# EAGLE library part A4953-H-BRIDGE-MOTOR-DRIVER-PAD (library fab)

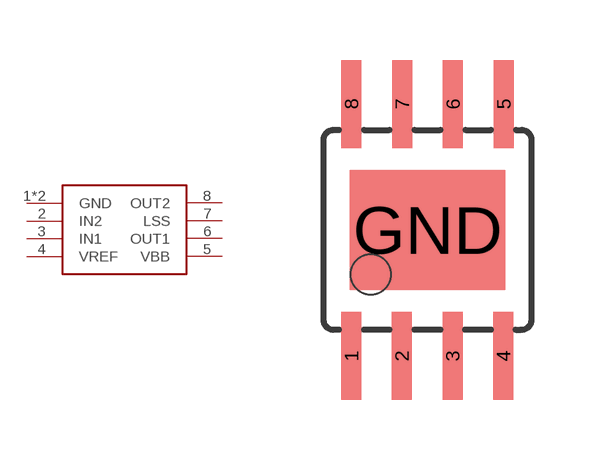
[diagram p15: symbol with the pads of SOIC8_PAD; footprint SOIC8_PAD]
Designator prefix -

## A4953-H-BRIDGE-MOTOR-DRIVER-PAD  [SOIC8_PAD]
1  GND
2  IN2
3  IN1
4  VREF
5  VBB
6  OUT1
7  LSS
8  OUT2
GND  GND

## Footprint SOIC8_PAD (pad centres in mm)
Wide Plastic Gull Wing Small Outline Package
smd 0.5 x 2.2: 1 -1.905,-3.154; 2 -0.645,-3.154; 3 0.625,-3.154; 4 1.895,-3.154; 5 1.905,3.154; 6 0.635,3.154; 7 -0.635,3.154; 8 -1.905,3.154
smd 3.886 x 2.997: GND 0,0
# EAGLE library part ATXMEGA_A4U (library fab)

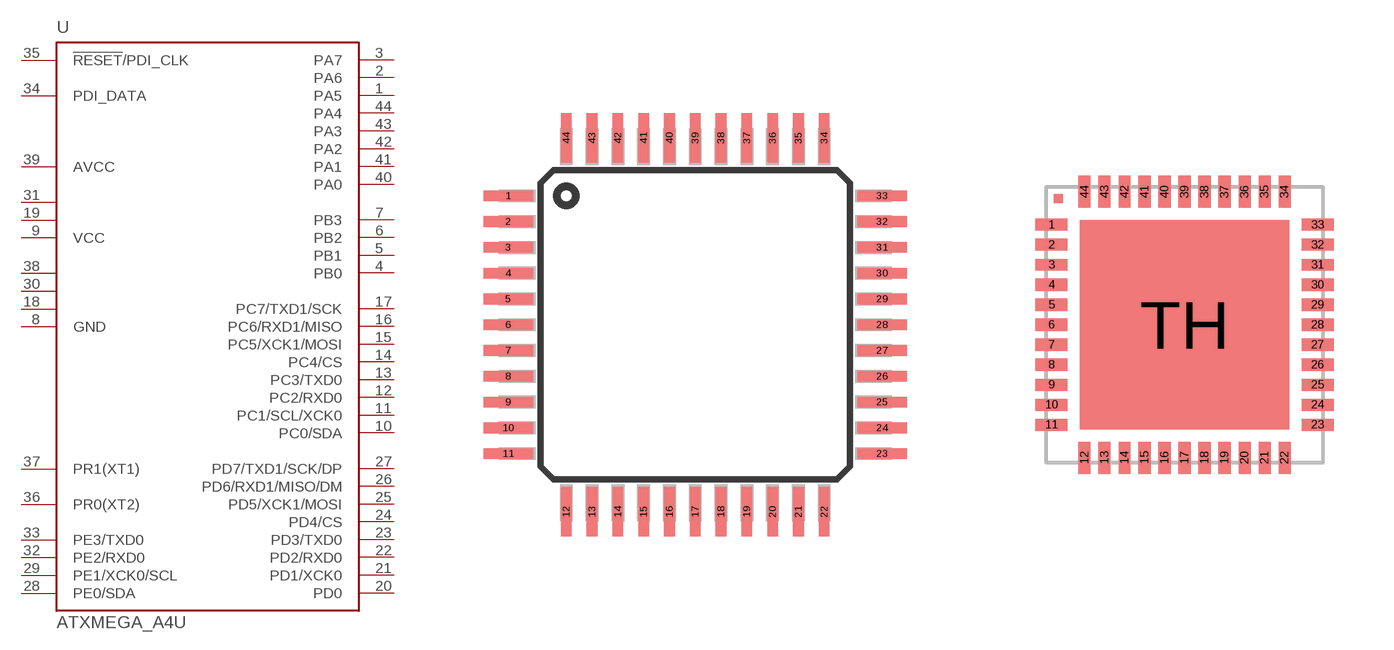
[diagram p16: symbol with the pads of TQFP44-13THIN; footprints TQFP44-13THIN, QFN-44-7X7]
Designator prefix -

## ATXMEGA_A4UTQFP-44-1-64  [TQFP44-13THIN]
1  PA5
2  PA6
3  PA7
4  PB0
5  PB1
6  PB2
7  PB3
8  GND  pwr
9  VCC  pwr
10  PC0/SDA
11  PC1/SCL/XCK0
12  PC2/RXD0
13  PC3/TXD0
14  PC4/CS
15  PC5/XCK1/MOSI
16  PC6/RXD1/MISO
17  PC7/TXD1/SCK
18  GND1  pwr
19  VCC1  pwr
20  PD0
21  PD1/XCK0
22  PD2/RXD0
23  PD3/TXD0
24  PD4/CS
25  PD5/XCK1/MOSI
26  PD6/RXD1/MISO/DM
27  PD7/TXD1/SCK/DP
28  PE0/SDA
29  PE1/XCK0/SCL
30  GND2  pwr
31  VCC2  pwr
32  PE2/RXD0
33  PE3/TXD0
34  PDI_DATA
35  !RESET!/PDI_CLK
36  PR0(XT2)
37  PR1(XT1)
38  GND3  pwr
39  AVCC  pwr
40  PA0
41  PA1
42  PA2
43  PA3
44  PA4

## ATXMEGA_A4UVFQFN-44  [QFN-44-7X7]
1  PA5
2  PA6
3  PA7
4  PB0
5  PB1
6  PB2
7  PB3
8  GND  pwr
9  VCC  pwr
10  PC0/SDA
11  PC1/SCL/XCK0
12  PC2/RXD0
13  PC3/TXD0
14  PC4/CS
15  PC5/XCK1/MOSI
16  PC6/RXD1/MISO
17  PC7/TXD1/SCK
18  GND1  pwr
19  VCC1  pwr
20  PD0
21  PD1/XCK0
22  PD2/RXD0
23  PD3/TXD0
24  PD4/CS
25  PD5/XCK1/MOSI
26  PD6/RXD1/MISO/DM
27  PD7/TXD1/SCK/DP
28  PE0/SDA
29  PE1/XCK0/SCL
30  GND2  pwr
31  VCC2  pwr
32  PE2/RXD0
33  PE3/TXD0
34  PDI_DATA
35  !RESET!/PDI_CLK
36  PR0(XT2)
37  PR1(XT1)
38  GND3  pwr
39  AVCC  pwr
40  PA0
41  PA1
42  PA2
43  PA3
44  PA4
TH  GND  pwr

## Footprint TQFP44-13THIN (pad centres in mm)
Thin Quad Flat Pack package type TQ
smd 1.524 x 0.33: 1 -5.8,4; 2 -5.8,3.2; 3 -5.8,2.4; 4 -5.8,1.6; 5 -5.8,0.8; 6 -5.8,0; 7 -5.8,-0.8; 8 -5.8,-1.6; 9 -5.8,-2.4; 10 -5.8,-3.2; 11 -5.8,-4; 23 5.8,-4; 24 5.8,-3.2; 25 5.8,-2.4; 26 5.8,-1.6; 27 5.8,-0.8; 28 5.8,0; 29 5.8,0.8; 30 5.8,1.6; 31 5.8,2.4; 32 5.8,3.2; 33 5.8,4
smd 0.33 x 1.524: 12 -4,-5.8; 13 -3.2,-5.8; 14 -2.4,-5.8; 15 -1.6,-5.8; 16 -0.8,-5.8; 17 0,-5.8; 18 0.8,-5.8; 19 1.6,-5.8; 20 2.4,-5.8; 21 3.2,-5.8; 22 4,-5.8; 34 4,5.8; 35 3.2,5.8; 36 2.4,5.8; 37 1.6,5.8; 38 0.8,5.8; 39 0,5.8; 40 -0.8,5.8; 41 -1.6,5.8; 42 -2.4,5.8; 43 -3.2,5.8; 44 -4,5.8

## Footprint QFN-44-7X7 (pad centres in mm)
QFN-44 (7x7x1.8mm) Source: http://www.st.com/stonline/products/literature/ds/11020.pdf
smd 0.8 x 0.3: 1 -3.325,2.5; 2 -3.325,2; 3 -3.325,1.5; 4 -3.325,1; 5 -3.325,0.5; 6 -3.325,0; 7 -3.325,-0.5; 8 -3.325,-1; 9 -3.325,-1.5; 10 -3.325,-2; 11 -3.325,-2.5; 23 3.325,-2.5; 24 3.325,-2; 25 3.325,-1.5; 26 3.325,-1; 27 3.325,-0.5; 28 3.325,0; 29 3.325,0.5; 30 3.325,1; 31 3.325,1.5; 32 3.325,2; 33 3.325,2.5
smd 0.3 x 0.8: 12 -2.5,-3.325; 13 -2,-3.325; 14 -1.5,-3.325; 15 -1,-3.325; 16 -0.5,-3.325; 17 0,-3.325; 18 0.5,-3.325; 19 1,-3.325; 20 1.5,-3.325; 21 2,-3.325; 22 2.5,-3.325; 34 2.5,3.325; 35 2,3.325; 36 1.5,3.325; 37 1,3.325; 38 0.5,3.325; 39 0,3.325; 40 -0.5,3.325; 41 -1,3.325; 42 -1.5,3.325; 43 -2,3.325; 44 -2.5,3.325
smd 5.24 x 5.24: TH 0,0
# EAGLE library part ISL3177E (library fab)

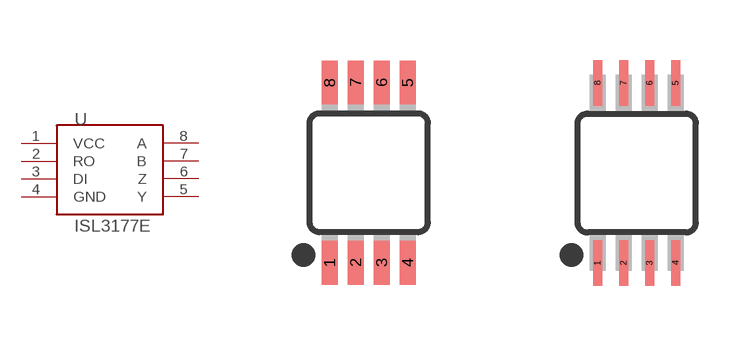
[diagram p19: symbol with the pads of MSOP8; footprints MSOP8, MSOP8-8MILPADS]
Designator prefix U

## ISL3177E  [MSOP8]
1  VCC
2  RO
3  DI
4  GND
5  Y
6  Z
7  B
8  A

## ISL3177EMILL  [MSOP8-8MILPADS]
Pads as for MSOP8

## Footprint MSOP8 (pad centres in mm)
8M, 8-Lead, 0.118" Wide, Miniature Small Outline Package MSOP 8M-Package doc1097.pdf
smd 0.4 x 1.1: 1 -0.975,-2.25; 2 -0.325,-2.25; 3 0.325,-2.25; 4 0.975,-2.25; 5 0.975,2.25; 6 0.325,2.25; 7 -0.325,2.25; 8 -0.975,2.25

## Footprint MSOP8-8MILPADS (pad centres in mm)
8M, 8-Lead, 0.118" Wide, Miniature Small Outline Package MSOP 8M-Package doc1097.pdf
smd 0.229 x 1.143: 1 -0.975,-2.25; 2 -0.325,-2.25; 3 0.325,-2.25; 4 0.975,-2.25; 5 0.975,2.25; 6 0.325,2.25; 7 -0.325,2.25; 8 -0.975,2.25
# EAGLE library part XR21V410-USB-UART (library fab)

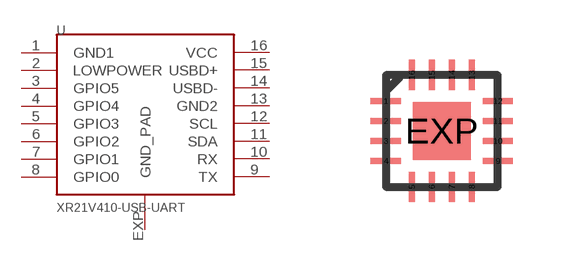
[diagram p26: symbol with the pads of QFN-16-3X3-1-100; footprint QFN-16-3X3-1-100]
Designator prefix -

## XR21V410-USB-UART  [QFN-16-3X3-1-100]
1  GND1
2  LOWPOWER
3  GPIO5
4  GPIO4
5  GPIO3
6  GPIO2
7  GPIO1
8  GPIO0
9  TX
10  RX
11  SDA
12  SCL
13  GND2
14  USBD-
15  USBD+
16  VCC
EXP  GND_PAD

## Footprint QFN-16-3X3-1-100 (pad centres in mm)
16-Lead Plastic QFN (3mm × 3mm) Auto generated by make-symbol-device-package-bsdl.ulp Rev. 44 Source: http://cds.linear.com/docs/en/datasheet/3645f.pdf
smd 0.762 x 0.152: 1 -1.4,0.75; 2 -1.4,0.25; 3 -1.4,-0.25; 4 -1.4,-0.75; 9 1.4,-0.75; 10 1.4,-0.25; 11 1.4,0.25; 12 1.4,0.75
smd 0.152 x 0.762: 5 -0.75,-1.4; 6 -0.25,-1.4; 7 0.25,-1.4; 8 0.75,-1.4; 13 0.75,1.4; 14 0.25,1.4; 15 -0.25,1.4; 16 -0.75,1.4
smd 1.45 x 1.45: EXP 0,0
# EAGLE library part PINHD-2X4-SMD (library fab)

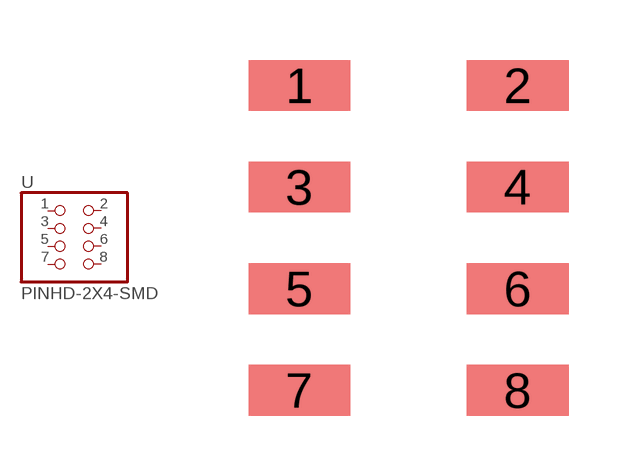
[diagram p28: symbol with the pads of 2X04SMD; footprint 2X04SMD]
Designator prefix -

## PINHD-2X4-SMD  [2X04SMD]
1  1  pas
2  2  pas
3  3  pas
4  4  pas
5  5  pas
6  6  pas
7  7  pas
8  8  pas

## Footprint 2X04SMD (pad centres in mm)
smd 2.54 x 1.27: 1 -2.54,3.81; 2 2.92,3.81; 3 -2.54,1.27; 4 2.92,1.27; 5 -2.54,-1.27; 6 2.92,-1.27; 7 -2.54,-3.81; 8 2.92,-3.81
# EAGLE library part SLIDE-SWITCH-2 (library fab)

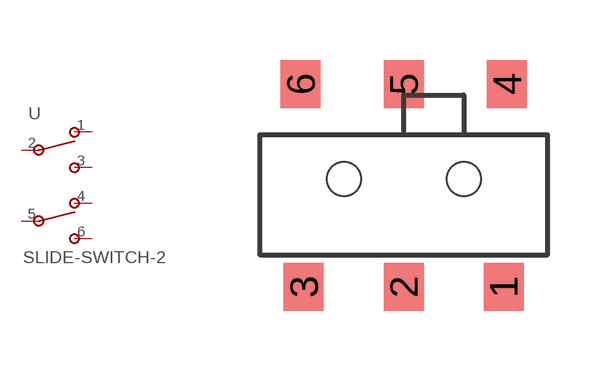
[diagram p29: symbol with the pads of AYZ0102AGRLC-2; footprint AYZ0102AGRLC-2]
Designator prefix -

## SLIDE-SWITCH-2  [AYZ0102AGRLC-2]
1  1
2  2
3  3
4  4
5  5
6  6

## Footprint AYZ0102AGRLC-2 (pad centres in mm)
smd 1 x 1.2: 1 2.5,-2.3; 2 0,-2.3; 3 -2.5,-2.3; 4 2.58,2.78; 5 0,2.78; 6 -2.58,2.78
hole 0.85 at -1.5,0.4
hole 0.85 at 1.5,0.4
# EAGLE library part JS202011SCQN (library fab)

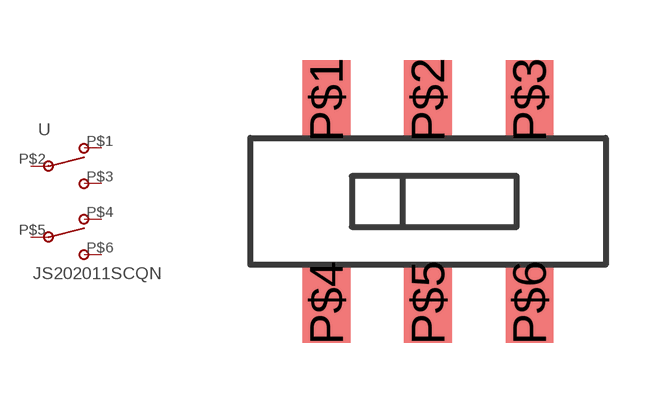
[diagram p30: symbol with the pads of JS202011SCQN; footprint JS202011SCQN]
Designator prefix -

## JS202011SCQN  [JS202011SCQN]
P$1  1
P$2  2
P$3  3
P$4  4
P$5  5
P$6  6

## Footprint JS202011SCQN (pad centres in mm)
smd 1.194 x 2.007: P$1 -2.54,2.54; P$2 0,2.54; P$3 2.54,2.54; P$4 -2.54,-2.54; P$5 0,-2.54; P$6 2.54,-2.54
